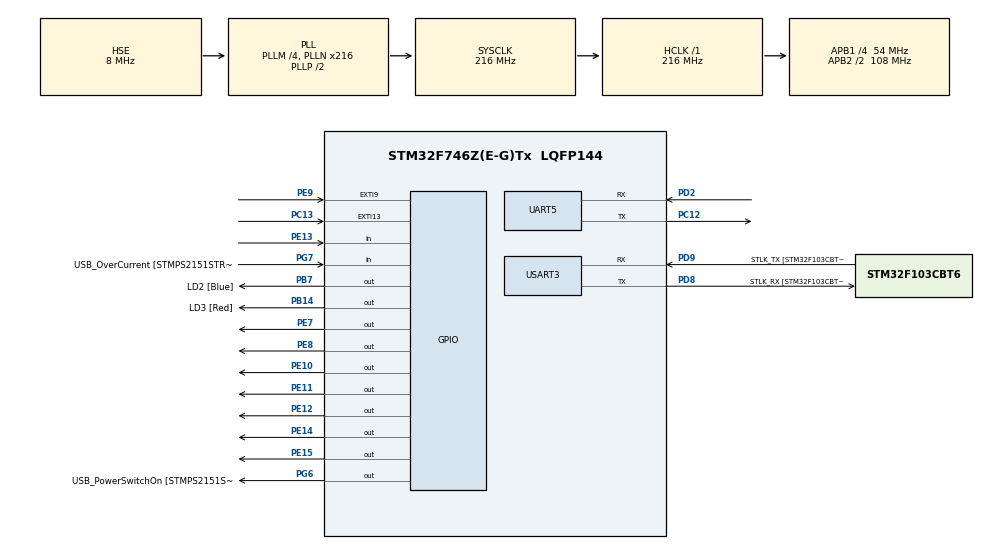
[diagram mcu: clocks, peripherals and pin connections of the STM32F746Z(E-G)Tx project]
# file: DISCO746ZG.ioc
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Mcu.Family=STM32F7
Mcu.Name=STM32F746Z(E-G)Tx
Mcu.Package=LQFP144
NVIC.EXTI15_10_IRQn=true\:0\:0\:false\:false\:true
NVIC.EXTI9_5_IRQn=true\:0\:0\:false\:false\:true
NVIC.PriorityGroup=NVIC_PRIORITYGROUP_4
NVIC.RCC_IRQn=true\:0\:0\:false\:false\:true
NVIC.TIM3_IRQn=true\:0\:0\:false\:false\:true
NVIC.TIM4_IRQn=true\:0\:0\:false\:false\:true
NVIC.TIM5_IRQn=true\:0\:0\:false\:false\:true
NVIC.UART5_IRQn=true\:0\:0\:false\:false\:true
NVIC.USART3_IRQn=true\:0\:0\:false\:false\:true
PA1.GPIO_Label=RMII_REF_CK [LAN8742A-CZ-TR_REFCLK0]
PA1.Signal=ETH_REF_CLK
PA10.GPIO_Label=USB_ID
PA10.Signal=USB_OTG_FS_ID
PA11.GPIO_Label=USB_DM
PA11.Signal=USB_OTG_FS_DM
PA12.GPIO_Label=USB_DP
PA12.Signal=USB_OTG_FS_DP
PA13.GPIO_Label=TMS
PA13.Signal=SYS_JTMS-SWDIO
PA14.GPIO_Label=TCK
PA14.Signal=SYS_JTCK-SWCLK
PA2.GPIO_Label=RMII_MDIO [LAN8742A-CZ-TR_MDIO]
PA2.Signal=ETH_MDIO
PA7.GPIO_Label=RMII_CRS_DV [LAN8742A-CZ-TR_CRS_DV]
PA7.Signal=ETH_CRS_DV
PA8.GPIO_Label=USB_SOF [TP1]
PA8.Signal=USB_OTG_FS_SOF
PA9.GPIO_Label=USB_VBUS
PA9.Signal=USB_OTG_FS_VBUS
PB13.GPIO_Label=RMII_TXD1 [LAN8742A-CZ-TR_TXD1]
PB13.Signal=ETH_TXD1
PB14.GPIO_Label=LD3 [Red]
PB14.Signal=GPIO_Output
PB3.GPIO_Label=SW0
PB3.Signal=SYS_JTDO-SWO
PB7.GPIO_Label=LD2 [Blue]
PB7.Signal=GPIO_Output
PC1.GPIO_Label=RMII_MDC [LAN8742A-CZ-TR_MDC]
PC1.Signal=ETH_MDC
PC12.Mode=Asynchronous
PC12.Signal=UART5_TX
PC13.GPIO_ModeDefaultEXTI=GPIO_MODE_IT_RISING_FALLING
PC13.Signal=GPXTI13
PC14/OSC32_IN.Mode=LSE-External-Oscillator
PC14/OSC32_IN.Signal=RCC_OSC32_IN
PC15/OSC32_OUT.Mode=LSE-External-Oscillator
PC15/OSC32_OUT.Signal=RCC_OSC32_OUT
PC4.GPIO_Label=RMII_RXD0 [LAN8742A-CZ-TR_RXD0]
PC4.Signal=ETH_RXD0
PC5.GPIO_Label=RMII_RXD1 [LAN8742A-CZ-TR_RXD1]
PC5.Signal=ETH_RXD1
PD2.Mode=Asynchronous
PD2.Signal=UART5_RX
PD8.GPIO_Label=STLK_RX [STM32F103CBT6_PA3]
PD8.Mode=Asynchronous
PD8.Signal=USART3_TX
PD9.GPIO_Label=STLK_TX [STM32F103CBT6_PA2]
PD9.Mode=Asynchronous
PD9.Signal=USART3_RX
PE10.Signal=GPIO_Output
PE11.Signal=GPIO_Output
PE12.Signal=GPIO_Output
PE13.Signal=GPIO_Input
PE14.Signal=GPIO_Output
PE15.Signal=GPIO_Output
PE7.Signal=GPIO_Output
PE8.Signal=GPIO_Output
PE9.GPIO_ModeDefaultEXTI=GPIO_MODE_IT_RISING_FALLING
PE9.GPIO_PuPd=GPIO_PULLDOWN
PE9.Signal=GPXTI9
PG11.GPIO_Label=RMII_TX_EN [LAN8742A-CZ-TR_TXEN]
PG11.Signal=ETH_TX_EN
PG13.GPIO_Label=RMII_TXD0 [LAN8742A-CZ-TR_TXD0]
PG13.Signal=ETH_TXD0
PG6.GPIO_Label=USB_PowerSwitchOn [STMPS2151STR_EN]
PG6.Signal=GPIO_Output
PG7.GPIO_Label=USB_OverCurrent [STMPS2151STR_FAULT]
PG7.Signal=GPIO_Input
PH0/OSC_IN.GPIO_Label=MCO [STM32F103CBT6_PA8]
PH0/OSC_IN.Mode=HSE-External-Oscillator
PH0/OSC_IN.Signal=RCC_OSC_IN
PH1/OSC_OUT.Mode=HSE-External-Oscillator
PH1/OSC_OUT.Signal=RCC_OSC_OUT
ProjectManager.HeapSize=0x200
ProjectManager.StackSize=0x400
ProjectManager.TargetToolchain=TrueSTUDIO
RCC.48MHZClocksFreq_Value=24000000
RCC.AHBFreq_Value=216000000
RCC.APB1CLKDivider=RCC_HCLK_DIV4
RCC.APB1Freq_Value=54000000
RCC.APB1TimFreq_Value=108000000
RCC.APB2CLKDivider=RCC_HCLK_DIV2
RCC.APB2Freq_Value=108000000
RCC.APB2TimFreq_Value=216000000
RCC.CortexFreq_Value=216000000
RCC.HCLKFreq_Value=216000000
RCC.HSE_VALUE=8000000
RCC.HSI_VALUE=8000000
RCC.PLLM=4
RCC.PLLMUL=RCC_PLL_MUL9
RCC.PLLN=216
RCC.PLLSourceVirtual=RCC_PLLSOURCE_HSE
RCC.PRESCALERUSB=RCC_USBCLKSOURCE_PLL_DIV1_5
RCC.SYSCLKFreq_VALUE=216000000
RCC.SYSCLKSource=RCC_SYSCLKSOURCE_PLLCLK
RCC.SYSCLKSourceVirtual=RCC_SYSCLKSOURCE_PLLCLK
RCC.USBFreq_Value=216000000
RCC.VCOOutputFreq_Value=432000000
TIM3.Period=9999
TIM3.Prescaler=10800
TIM4.Period=4999
TIM4.Prescaler=10800
TIM5.Period=2499
TIM5.Prescaler=10800
UART5.WordLength=UART_WORDLENGTH_8B
USART3.WordLength=UART_WORDLENGTH_8B
VP_TIM3_VS_ClockSourceINT.Mode=Internal
VP_TIM4_VS_ClockSourceINT.Mode=Internal
VP_TIM5_VS_ClockSourceINT.Mode=Internal
board=NUCLEO-F746ZG

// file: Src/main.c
/**
  ******************************************************************************
  * File Name          : main.c
  * Description        : Main program body
  ******************************************************************************
  *
  * COPYRIGHT(c) 2016 STMicroelectronics
  *
  * Redistribution and use in source and binary forms, with or without modification,
  * are permitted provided that the following conditions are met:
  *   1. Redistributions of source code must retain the above copyright notice,
  *      this list of conditions and the following disclaimer.
  *   2. Redistributions in binary form must reproduce the above copyright notice,
  *      this list of conditions and the following disclaimer in the documentation
  *      and/or other materials provided with the distribution.
  *   3. Neither the name of STMicroelectronics nor the names of its contributors
  *      may be used to endorse or promote products derived from this software
  *      without specific prior written permission.
  *
  * THIS SOFTWARE IS PROVIDED BY THE COPYRIGHT HOLDERS AND CONTRIBUTORS "AS IS"
  * AND ANY EXPRESS OR IMPLIED WARRANTIES, INCLUDING, BUT NOT LIMITED TO, THE
  * IMPLIED WARRANTIES OF MERCHANTABILITY AND FITNESS FOR A PARTICULAR PURPOSE ARE
  * DISCLAIMED. IN NO EVENT SHALL THE COPYRIGHT HOLDER OR CONTRIBUTORS BE LIABLE
  * FOR ANY DIRECT, INDIRECT, INCIDENTAL, SPECIAL, EXEMPLARY, OR CONSEQUENTIAL
  * DAMAGES (INCLUDING, BUT NOT LIMITED TO, PROCUREMENT OF SUBSTITUTE GOODS OR
  * SERVICES; LOSS OF USE, DATA, OR PROFITS; OR BUSINESS INTERRUPTION) HOWEVER
  * CAUSED AND ON ANY THEORY OF LIABILITY, WHETHER IN CONTRACT, STRICT LIABILITY,
  * OR TORT (INCLUDING NEGLIGENCE OR OTHERWISE) ARISING IN ANY WAY OUT OF THE USE
  * OF THIS SOFTWARE, EVEN IF ADVISED OF THE POSSIBILITY OF SUCH DAMAGE.
  *
  ******************************************************************************
  */
#include "stm32f7xx_hal.h"

/* USER CODE BEGIN Includes */
// 주의사항 : Systick은 반드시 1/1000000
#include <stdio.h>
#include <stdint.h>
#include <math.h>
#include "tlcd.h"

/* USER CODE END Includes */

TIM_HandleTypeDef htim3;
TIM_HandleTypeDef htim4;
TIM_HandleTypeDef htim5;

UART_HandleTypeDef huart5;
UART_HandleTypeDef huart3;

/* USER CODE BEGIN PV */
/* Private variables ---------------------------------------------------------*/
#define DATA  10
#define PI 	  3.141592
uint8_t Rx_Buffer3[DATA];
uint8_t Rx_Buffer4[DATA];
uint8_t Rx_Buffer5[DATA];

uint8_t Rx_Data3[2];
uint8_t Rx_Data4[2];
uint8_t Rx_Data5[2];

uint8_t Rx_Indx3;
uint8_t Rx_Indx4;
uint8_t Rx_Indx5;

uint8_t Transfer_cplt3;
uint8_t Transfer_cplt4;
uint8_t Transfer_cplt5;

__IO uint8_t	n=0;
/* USER CODE END PV */

void SystemClock_Config(void);
static void MX_GPIO_Init(void);
static void MX_TIM3_Init(void);
static void MX_TIM4_Init(void);
static void MX_TIM5_Init(void);
static void MX_UART5_Init(void);
static void MX_USART3_UART_Init(void);

/* USER CODE BEGIN PFP */
/* Private function prototypes -----------------------------------------------*/
void 		HAL_TIM_PeriodElapsedCallback(TIM_HandleTypeDef *htim);
void 		HAL_UART_RxCpltCallback(UART_HandleTypeDef *huart);
void 		HAL_GPIO_EXTI_Callback(uint16_t GPIO_Pin);
void		MathDelay();
/* USER CODE END PFP */

/* USER CODE BEGIN 0 */
void	MathDelay()
{
	volatile uint32_t a;
	double	 d2;

	for(a=0;a<1000000;a++)
	{
		d2 = sin(a*3.141592/180) * cos(a*3.141592/180);
	}
	HAL_UART_Transmit(&huart3, (uint8_t *)"@\r\n", 3,1000);
}

void HAL_GPIO_EXTI_Callback(uint16_t GPIO_Pin)
{
	char s[20];

			sprintf(s,"Pin no : %5d\r\n",GPIO_Pin);
			HAL_UART_Transmit(&huart3, (uint8_t *)s,16 ,1000);
}

void HAL_TIM_PeriodElapsedCallback(TIM_HandleTypeDef *htim)
{
	// call back 함수내에서 절대 static변수 사용하지 말것....
	char		Tdata1[20],Tdata2[20],Tdata3[20];

	if(htim->Instance==TIM3) {
		HAL_GPIO_TogglePin(GPIOB,  GPIO_PIN_15 | GPIO_PIN_0);
	    //sprintf(Tdata1,"%3d : %10.5lf\r\n",n,sin(n*PI/180));
		//HAL_UART_Transmit(&huart3, (uint8_t *)Tdata1,18 ,1000);
	}
	else if(htim->Instance==TIM4) {
		HAL_GPIO_TogglePin(GPIOB,  LD2_Pin | GPIO_PIN_13);
	    //sprintf(Tdata2,"%3d : %10.5lf\r\n",n,cos(n*PI/180));
		//HAL_UART_Transmit(&huart3, (uint8_t *)Tdata2,18 ,1000);
	}
	else if(htim->Instance==TIM5) {
		HAL_GPIO_TogglePin(GPIOB,  LD3_Pin | GPIO_PIN_12);
	    //sprintf(Tdata3,"%3d : %10.5lf\r\n",n,exp(n*PI/180));
		//HAL_UART_Transmit(&huart3, (uint8_t *)Tdata3,18 ,1000);
	}
	if(++n==91) n = 0;

}

void HAL_UART_RxCpltCallback(UART_HandleTypeDef *huart)
{
	uint8_t	i;

	if(huart->Instance==USART3)
	{
		if(Rx_Indx3==0)
		{
			for(i=0;i<DATA;i++) Rx_Buffer3[i] = 0;
		}
		if(Rx_Data3[0]!=0x0d)
		{
			Rx_Buffer3[Rx_Indx3++]=Rx_Data3[0];
		}
		else
		{
			Rx_Indx3 = 0;
			Transfer_cplt3 = 1;
		}
		HAL_UART_Receive_IT(&huart3, Rx_Data3, 1);
		HAL_UART_Transmit(&huart3, Rx_Data3, 1,1000);
	}
	/* else if(huart->Instance==UART4)
	{
		if(Rx_Indx4==0)
		{
			for(i=0;i<DATA;i++) Rx_Buffer4[i] = 0;
		}
		if(Rx_Data4[0]!=0x0d)
		{
			Rx_Buffer4[Rx_Indx4++]=Rx_Data4[0];
		}
		else
		{
			Rx_Indx4 = 0;
			Transfer_cplt4 = 1;
		}
		HAL_UART_Receive_IT(&huart4, Rx_Data4, 1);
		HAL_UART_Transmit(&huart4, Rx_Data4, 1,1000);
	} */
	else if(huart->Instance==UART5)
	{
		if(Rx_Indx5==0)
		{
			for(i=0;i<DATA;i++) Rx_Buffer5[i] = 0;
		}
		if(Rx_Data5[0]!=0x0d)
		{
			Rx_Buffer5[Rx_Indx5++]=Rx_Data5[0];
		}
		else
		{
			Rx_Indx5 = 0;
			Transfer_cplt5 = 1;
		}
		HAL_UART_Receive_IT(&huart5, Rx_Data5, 1);
		HAL_UART_Transmit(&huart5, Rx_Data5, 1,1000);
	}
}

/* USER CODE END 0 */

int main(void)
{

  /* USER CODE BEGIN 1 */
	uint16_t u=0;
	char     lcd_data[16];
  /* USER CODE END 1 */

  /* MCU Configuration----------------------------------------------------------*/

  /* Reset of all peripherals, Initializes the Flash interface and the Systick. */
  HAL_Init();

  /* Configure the system clock */
  SystemClock_Config();

  /* Initialize all configured peripherals */
  MX_GPIO_Init();
  MX_TIM3_Init();
  MX_TIM4_Init();
  MX_TIM5_Init();
  MX_UART5_Init();
  MX_USART3_UART_Init();

  /* USER CODE BEGIN 2 */
	while(HAL_TIM_Base_Start_IT(&htim3)!=HAL_OK);
	while(HAL_TIM_Base_Start_IT(&htim4)!=HAL_OK);
	while(HAL_TIM_Base_Start_IT(&htim5)!=HAL_OK);

	while(HAL_UART_Receive_IT(&huart3, Rx_Data3, 1)!=HAL_OK);
	while(HAL_UART_Receive_IT(&huart5, Rx_Data5, 1)!=HAL_OK);

	HAL_UART_Transmit(&huart3, (uint8_t *)"Test Program\r\n",14 ,1000);

	TLCD_Init(GPIO_PIN_7,GPIO_PIN_8,GPIO_PIN_10,GPIO_PIN_12,GPIO_PIN_14,GPIO_PIN_15);
	//           1234567890123456
	TLCD_Puts(1,"* Cortex-M7");
	TLCD_Puts(2,"* Cortex-M7");
	HAL_Delay(3000000);
  /* USER CODE END 2 */

  /* Infinite loop */
  while (1)
  {

  /* USER CODE BEGIN 3 */
	  sprintf(lcd_data,"Data = %05d",u);
		TLCD_Puts(1,lcd_data);
	  sprintf(lcd_data,"Code = %05d",u);
		TLCD_Puts(2,lcd_data);
		u++;
	  if(u>9999) u=0;
	  MathDelay();
	  //HAL_Delay(100000);
  }
  /* USER CODE END 3 */

}

/** System Clock Configuration
*/
void SystemClock_Config(void)
{

  RCC_OscInitTypeDef RCC_OscInitStruct;
  RCC_ClkInitTypeDef RCC_ClkInitStruct;
  RCC_PeriphCLKInitTypeDef PeriphClkInitStruct;

  __HAL_RCC_PWR_CLK_ENABLE();

  __HAL_PWR_VOLTAGESCALING_CONFIG(PWR_REGULATOR_VOLTAGE_SCALE1);

  RCC_OscInitStruct.OscillatorType = RCC_OSCILLATORTYPE_HSE;
  RCC_OscInitStruct.HSEState = RCC_HSE_ON;
  RCC_OscInitStruct.PLL.PLLState = RCC_PLL_ON;
  RCC_OscInitStruct.PLL.PLLSource = RCC_PLLSOURCE_HSE;
  RCC_OscInitStruct.PLL.PLLM = 4;
  RCC_OscInitStruct.PLL.PLLN = 216;
  RCC_OscInitStruct.PLL.PLLP = RCC_PLLP_DIV2;
  RCC_OscInitStruct.PLL.PLLQ = 2;
  HAL_RCC_OscConfig(&RCC_OscInitStruct);

  HAL_PWREx_EnableOverDrive();

  RCC_ClkInitStruct.ClockType = RCC_CLOCKTYPE_HCLK|RCC_CLOCKTYPE_SYSCLK
                              |RCC_CLOCKTYPE_PCLK1|RCC_CLOCKTYPE_PCLK2;
  RCC_ClkInitStruct.SYSCLKSource = RCC_SYSCLKSOURCE_PLLCLK;
  RCC_ClkInitStruct.AHBCLKDivider = RCC_SYSCLK_DIV1;
  RCC_ClkInitStruct.APB1CLKDivider = RCC_HCLK_DIV4;
  RCC_ClkInitStruct.APB2CLKDivider = RCC_HCLK_DIV2;
  HAL_RCC_ClockConfig(&RCC_ClkInitStruct, FLASH_LATENCY_7);

  PeriphClkInitStruct.PeriphClockSelection = RCC_PERIPHCLK_USART3|RCC_PERIPHCLK_UART5;
  PeriphClkInitStruct.Usart3ClockSelection = RCC_USART3CLKSOURCE_PCLK1;
  PeriphClkInitStruct.Uart5ClockSelection = RCC_UART5CLKSOURCE_PCLK1;
  HAL_RCCEx_PeriphCLKConfig(&PeriphClkInitStruct);

  HAL_SYSTICK_Config(HAL_RCC_GetHCLKFreq()/1000000);

  HAL_SYSTICK_CLKSourceConfig(SYSTICK_CLKSOURCE_HCLK);

  /* SysTick_IRQn interrupt configuration */
  HAL_NVIC_SetPriority(SysTick_IRQn, 0, 0);
}

/* TIM3 init function */
void MX_TIM3_Init(void)
{

  TIM_ClockConfigTypeDef sClockSourceConfig;
  TIM_MasterConfigTypeDef sMasterConfig;

  htim3.Instance = TIM3;
  htim3.Init.Prescaler = 10800;
  htim3.Init.CounterMode = TIM_COUNTERMODE_UP;
  htim3.Init.Period = 9999;
  htim3.Init.ClockDivision = TIM_CLOCKDIVISION_DIV1;
  HAL_TIM_Base_Init(&htim3);

  sClockSourceConfig.ClockSource = TIM_CLOCKSOURCE_INTERNAL;
  HAL_TIM_ConfigClockSource(&htim3, &sClockSourceConfig);

  sMasterConfig.MasterOutputTrigger = TIM_TRGO_RESET;
  sMasterConfig.MasterSlaveMode = TIM_MASTERSLAVEMODE_DISABLE;
  HAL_TIMEx_MasterConfigSynchronization(&htim3, &sMasterConfig);

}

/* TIM4 init function */
void MX_TIM4_Init(void)
{

  TIM_ClockConfigTypeDef sClockSourceConfig;
  TIM_MasterConfigTypeDef sMasterConfig;

  htim4.Instance = TIM4;
  htim4.Init.Prescaler = 10800;
  htim4.Init.CounterMode = TIM_COUNTERMODE_UP;
  htim4.Init.Period = 4999;
  htim4.Init.ClockDivision = TIM_CLOCKDIVISION_DIV1;
  HAL_TIM_Base_Init(&htim4);

  sClockSourceConfig.ClockSource = TIM_CLOCKSOURCE_INTERNAL;
  HAL_TIM_ConfigClockSource(&htim4, &sClockSourceConfig);

  sMasterConfig.MasterOutputTrigger = TIM_TRGO_RESET;
  sMasterConfig.MasterSlaveMode = TIM_MASTERSLAVEMODE_DISABLE;
  HAL_TIMEx_MasterConfigSynchronization(&htim4, &sMasterConfig);

}

/* TIM5 init function */
void MX_TIM5_Init(void)
{

  TIM_ClockConfigTypeDef sClockSourceConfig;
  TIM_MasterConfigTypeDef sMasterConfig;

  htim5.Instance = TIM5;
  htim5.Init.Prescaler = 10800;
  htim5.Init.CounterMode = TIM_COUNTERMODE_UP;
  htim5.Init.Period = 2499;
  htim5.Init.ClockDivision = TIM_CLOCKDIVISION_DIV1;
  HAL_TIM_Base_Init(&htim5);

  sClockSourceConfig.ClockSource = TIM_CLOCKSOURCE_INTERNAL;
  HAL_TIM_ConfigClockSource(&htim5, &sClockSourceConfig);

  sMasterConfig.MasterOutputTrigger = TIM_TRGO_RESET;
  sMasterConfig.MasterSlaveMode = TIM_MASTERSLAVEMODE_DISABLE;
  HAL_TIMEx_MasterConfigSynchronization(&htim5, &sMasterConfig);

}

/* UART5 init function */
void MX_UART5_Init(void)
{

  huart5.Instance = UART5;
  huart5.Init.BaudRate = 115200;
  huart5.Init.WordLength = UART_WORDLENGTH_8B;
  huart5.Init.StopBits = UART_STOPBITS_1;
  huart5.Init.Parity = UART_PARITY_NONE;
  huart5.Init.Mode = UART_MODE_TX_RX;
  huart5.Init.HwFlowCtl = UART_HWCONTROL_NONE;
  huart5.Init.OverSampling = UART_OVERSAMPLING_16;
  huart5.Init.OneBitSampling = UART_ONE_BIT_SAMPLE_DISABLE;
  huart5.AdvancedInit.AdvFeatureInit = UART_ADVFEATURE_NO_INIT;
  HAL_UART_Init(&huart5);

}

/* USART3 init function */
void MX_USART3_UART_Init(void)
{

  huart3.Instance = USART3;
  huart3.Init.BaudRate = 115200;
  huart3.Init.WordLength = UART_WORDLENGTH_8B;
  huart3.Init.StopBits = UART_STOPBITS_1;
  huart3.Init.Parity = UART_PARITY_NONE;
  huart3.Init.Mode = UART_MODE_TX_RX;
  huart3.Init.HwFlowCtl = UART_HWCONTROL_NONE;
  huart3.Init.OverSampling = UART_OVERSAMPLING_16;
  huart3.Init.OneBitSampling = UART_ONE_BIT_SAMPLE_DISABLE;
  huart3.AdvancedInit.AdvFeatureInit = UART_ADVFEATURE_NO_INIT;
  HAL_UART_Init(&huart3);

}

/** Configure pins as
        * Analog
        * Input
        * Output
        * EVENT_OUT
        * EXTI
     PC1   ------> ETH_MDC
     PA1   ------> ETH_REF_CLK
     PA2   ------> ETH_MDIO
     PA7   ------> ETH_CRS_DV
     PC4   ------> ETH_RXD0
     PC5   ------> ETH_RXD1
     PB13   ------> ETH_TXD1
     PA8   ------> USB_OTG_FS_SOF
     PA10   ------> USB_OTG_FS_ID
     PA11   ------> USB_OTG_FS_DM
     PA12   ------> USB_OTG_FS_DP
     PG11   ------> ETH_TX_EN
     PG13   ------> ETH_TXD0
*/
void MX_GPIO_Init(void)
{

  GPIO_InitTypeDef GPIO_InitStruct;

  /* GPIO Ports Clock Enable */
  __HAL_RCC_GPIOC_CLK_ENABLE();
  __HAL_RCC_GPIOH_CLK_ENABLE();
  __HAL_RCC_GPIOA_CLK_ENABLE();
  __HAL_RCC_GPIOE_CLK_ENABLE();
  __HAL_RCC_GPIOB_CLK_ENABLE();
  __HAL_RCC_GPIOD_CLK_ENABLE();
  __HAL_RCC_GPIOG_CLK_ENABLE();

  /*Configure GPIO pin : PC13 */
  GPIO_InitStruct.Pin = GPIO_PIN_13;
  GPIO_InitStruct.Mode = GPIO_MODE_IT_RISING;
  GPIO_InitStruct.Pull = GPIO_NOPULL;
  HAL_GPIO_Init(GPIOC, &GPIO_InitStruct);

  /*Configure GPIO pins : RMII_MDC_Pin RMII_RXD0_Pin RMII_RXD1_Pin */
  GPIO_InitStruct.Pin = RMII_MDC_Pin|RMII_RXD0_Pin|RMII_RXD1_Pin;
  GPIO_InitStruct.Mode = GPIO_MODE_AF_PP;
  GPIO_InitStruct.Pull = GPIO_NOPULL;
  GPIO_InitStruct.Speed = GPIO_SPEED_FREQ_VERY_HIGH;
  GPIO_InitStruct.Alternate = GPIO_AF11_ETH;
  HAL_GPIO_Init(GPIOC, &GPIO_InitStruct);

  /*Configure GPIO pins : RMII_REF_CK_Pin RMII_MDIO_Pin RMII_CRS_DV_Pin */
  GPIO_InitStruct.Pin = RMII_REF_CK_Pin|RMII_MDIO_Pin|RMII_CRS_DV_Pin;
  GPIO_InitStruct.Mode = GPIO_MODE_AF_PP;
  GPIO_InitStruct.Pull = GPIO_NOPULL;
  GPIO_InitStruct.Speed = GPIO_SPEED_FREQ_VERY_HIGH;
  GPIO_InitStruct.Alternate = GPIO_AF11_ETH;
  HAL_GPIO_Init(GPIOA, &GPIO_InitStruct);

  /*Configure GPIO pins : PE7 PE8 PE10 PE11
                           PE12 PE14 PE15 */
  GPIO_InitStruct.Pin = GPIO_PIN_7|GPIO_PIN_8|GPIO_PIN_10|GPIO_PIN_11
                          |GPIO_PIN_12|GPIO_PIN_14|GPIO_PIN_15;
  GPIO_InitStruct.Mode = GPIO_MODE_OUTPUT_PP;
  GPIO_InitStruct.Pull = GPIO_NOPULL;
  GPIO_InitStruct.Speed = GPIO_SPEED_FREQ_LOW;
  HAL_GPIO_Init(GPIOE, &GPIO_InitStruct);

  /*Configure GPIO pin : PE9 */
  GPIO_InitStruct.Pin = GPIO_PIN_9;
  GPIO_InitStruct.Mode = GPIO_MODE_IT_RISING;
  GPIO_InitStruct.Pull = GPIO_PULLDOWN; //
  HAL_GPIO_Init(GPIOE, &GPIO_InitStruct);

  /*Configure GPIO pin : PE13 */
  GPIO_InitStruct.Pin = GPIO_PIN_13;
  GPIO_InitStruct.Mode = GPIO_MODE_INPUT;
  GPIO_InitStruct.Pull = GPIO_NOPULL;
  HAL_GPIO_Init(GPIOE, &GPIO_InitStruct);

  /*Configure GPIO pin : RMII_TXD1_Pin */
  GPIO_InitStruct.Pin = RMII_TXD1_Pin;
  GPIO_InitStruct.Mode = GPIO_MODE_AF_PP;
  GPIO_InitStruct.Pull = GPIO_NOPULL;
  GPIO_InitStruct.Speed = GPIO_SPEED_FREQ_VERY_HIGH;
  GPIO_InitStruct.Alternate = GPIO_AF11_ETH;
  HAL_GPIO_Init(RMII_TXD1_GPIO_Port, &GPIO_InitStruct);

  /*Configure GPIO pins : LD3_Pin LD2_Pin */
  GPIO_InitStruct.Pin = LD3_Pin|LD2_Pin|GPIO_PIN_0|GPIO_PIN_15;
  GPIO_InitStruct.Mode = GPIO_MODE_OUTPUT_PP;
  GPIO_InitStruct.Pull = GPIO_NOPULL;
  GPIO_InitStruct.Speed = GPIO_SPEED_FREQ_LOW;
  HAL_GPIO_Init(GPIOB, &GPIO_InitStruct);

  /*Configure GPIO pin : USB_PowerSwitchOn_Pin */
  GPIO_InitStruct.Pin = USB_PowerSwitchOn_Pin;
  GPIO_InitStruct.Mode = GPIO_MODE_OUTPUT_PP;
  GPIO_InitStruct.Pull = GPIO_NOPULL;
  GPIO_InitStruct.Speed = GPIO_SPEED_FREQ_LOW;
  HAL_GPIO_Init(USB_PowerSwitchOn_GPIO_Port, &GPIO_InitStruct);

  /*Configure GPIO pin : USB_OverCurrent_Pin */
  GPIO_InitStruct.Pin = USB_OverCurrent_Pin;
  GPIO_InitStruct.Mode = GPIO_MODE_INPUT;
  GPIO_InitStruct.Pull = GPIO_NOPULL;
  HAL_GPIO_Init(USB_OverCurrent_GPIO_Port, &GPIO_InitStruct);

  /*Configure GPIO pins : USB_SOF_Pin USB_ID_Pin USB_DM_Pin USB_DP_Pin */
  GPIO_InitStruct.Pin = USB_SOF_Pin|USB_ID_Pin|USB_DM_Pin|USB_DP_Pin;
  GPIO_InitStruct.Mode = GPIO_MODE_AF_PP;
  GPIO_InitStruct.Pull = GPIO_NOPULL;
  GPIO_InitStruct.Speed = GPIO_SPEED_FREQ_VERY_HIGH;
  GPIO_InitStruct.Alternate = GPIO_AF10_OTG_FS;
  HAL_GPIO_Init(GPIOA, &GPIO_InitStruct);

  /*Configure GPIO pins : RMII_TX_EN_Pin RMII_TXD0_Pin */
  GPIO_InitStruct.Pin = RMII_TX_EN_Pin|RMII_TXD0_Pin;
  GPIO_InitStruct.Mode = GPIO_MODE_AF_PP;
  GPIO_InitStruct.Pull = GPIO_NOPULL;
  GPIO_InitStruct.Speed = GPIO_SPEED_FREQ_VERY_HIGH;
  GPIO_InitStruct.Alternate = GPIO_AF11_ETH;
  HAL_GPIO_Init(GPIOG, &GPIO_InitStruct);

  /*Configure GPIO pin Output Level */
  HAL_GPIO_WritePin(GPIOE, GPIO_PIN_7|GPIO_PIN_8|GPIO_PIN_10|GPIO_PIN_11
                          |GPIO_PIN_12|GPIO_PIN_14|GPIO_PIN_15, GPIO_PIN_RESET);

  /*Configure GPIO pin Output Level */
  HAL_GPIO_WritePin(GPIOB, LD3_Pin|LD2_Pin|GPIO_PIN_0|GPIO_PIN_15, GPIO_PIN_RESET);

  /*Configure GPIO pin Output Level */
  HAL_GPIO_WritePin(USB_PowerSwitchOn_GPIO_Port, USB_PowerSwitchOn_Pin, GPIO_PIN_RESET);

  /* EXTI interrupt init*/
  HAL_NVIC_SetPriority(EXTI9_5_IRQn, 0, 0);
  HAL_NVIC_EnableIRQ(EXTI9_5_IRQn);

  HAL_NVIC_SetPriority(EXTI15_10_IRQn, 0, 0);
  HAL_NVIC_EnableIRQ(EXTI15_10_IRQn);

}

/************************ (C) COPYRIGHT STMicroelectronics *****END OF FILE****/
